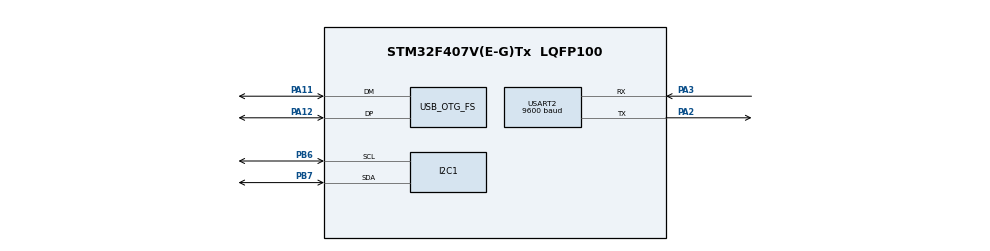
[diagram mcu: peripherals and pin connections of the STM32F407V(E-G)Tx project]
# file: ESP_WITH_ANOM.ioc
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Mcu.Family=STM32F4
Mcu.Name=STM32F407V(E-G)Tx
Mcu.Package=LQFP100
NVIC.OTG_FS_IRQn=true\:0\:0\:false\:false\:true\:true\:true\:true
NVIC.PriorityGroup=NVIC_PRIORITYGROUP_0
PA11.Mode=Device_Only
PA11.Signal=USB_OTG_FS_DM
PA12.Mode=Device_Only
PA12.Signal=USB_OTG_FS_DP
PA13.Mode=Serial_Wire
PA13.Signal=SYS_JTMS-SWDIO
PA14.Mode=Serial_Wire
PA14.Signal=SYS_JTCK-SWCLK
PA2.Mode=Asynchronous
PA2.Signal=USART2_TX
PA3.Mode=Asynchronous
PA3.Signal=USART2_RX
PB6.Mode=I2C
PB6.Signal=I2C1_SCL
PB7.Mode=I2C
PB7.Signal=I2C1_SDA
PH0-OSC_IN.Mode=HSE-External-Oscillator
PH0-OSC_IN.Signal=RCC_OSC_IN
PH1-OSC_OUT.Mode=HSE-External-Oscillator
PH1-OSC_OUT.Signal=RCC_OSC_OUT
ProjectManager.HeapSize=0x200
ProjectManager.StackSize=0x400
ProjectManager.TargetToolchain=STM32CubeIDE
RCC.48MHZClocksFreq_Value=48000000
RCC.AHBFreq_Value=168000000
RCC.APB1CLKDivider=RCC_HCLK_DIV4
RCC.APB1Freq_Value=42000000
RCC.APB1TimFreq_Value=84000000
RCC.APB2CLKDivider=RCC_HCLK_DIV2
RCC.APB2Freq_Value=84000000
RCC.APB2TimFreq_Value=168000000
RCC.CortexFreq_Value=168000000
RCC.HCLKFreq_Value=168000000
RCC.HSE_VALUE=8000000
RCC.HSI_VALUE=16000000
RCC.LSE_VALUE=32768
RCC.PLLM=8
RCC.PLLN=336
RCC.PLLQ=7
RCC.SYSCLKFreq_VALUE=168000000
RCC.SYSCLKSource=RCC_SYSCLKSOURCE_PLLCLK
RCC.VCOOutputFreq_Value=336000000
USART2.BaudRate=9600
USART2.Mode=MODE_TX
USART2.VirtualMode=VM_ASYNC
USB_DEVICE.CLASS_NAME_FS=CDC
USB_DEVICE.VirtualMode-CDC_FS=Cdc
USB_DEVICE.VirtualModeFS=Cdc_FS
USB_OTG_FS.VirtualMode=Device_Only
VP_USB_DEVICE_VS_USB_DEVICE_CDC_FS.Mode=CDC_FS
board=STM32F407G-DISC1

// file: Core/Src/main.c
/* USER CODE BEGIN Header */
/**
  ******************************************************************************
  * @file           : main.c
  * @brief          : Main program body (ADXL345 + USART2 for ESP32)
  ******************************************************************************
  */
/* USER CODE END Header */

#include "main.h"
#include "i2c.h"
#include "usart.h"
#include "gpio.h"

/* USER CODE BEGIN Includes */
#include <stdio.h>
#include <string.h>
#include <stdarg.h>
#include "NanoEdgeAI.h"
#include "knowledge.h"
/* USER CODE END Includes */

/* USER CODE BEGIN PTD */
typedef struct { int16_t x, y, z; } vector3_t;
/* USER CODE END PTD */

/* USER CODE BEGIN PD */
#define ADXL345_ADDR              (0x53 << 1)
#define ADXL345_REG_POWER_CTL     0x2D
#define ADXL345_REG_DATA_FORMAT   0x31
#define ADXL345_REG_DATA_X0       0x32
#define ACC_BUFFER_SIZE           300
/* USER CODE END PD */

/* USER CODE BEGIN PV */
float acc_buffer[ACC_BUFFER_SIZE];
/* USER CODE END PV */

void SystemClock_Config(void);
/* USER CODE BEGIN PFP */
void uart_printf(const char *fmt, ...);
HAL_StatusTypeDef Read_ADXL345(vector3_t *accel);
void fill_accelerometer_buffer(void);
/* USER CODE END PFP */

/* USER CODE BEGIN 0 */
void uart_printf(const char *fmt, ...) {
    char buffer[128];
    va_list args;
    va_start(args, fmt);
    vsnprintf(buffer, sizeof(buffer), fmt, args);
    va_end(args);
    HAL_UART_Transmit(&huart2, (uint8_t *)buffer, strlen(buffer), HAL_MAX_DELAY);
    HAL_Delay(5);
}

HAL_StatusTypeDef Read_ADXL345(vector3_t *accel) {
    uint8_t buf[6];
    if (HAL_I2C_Mem_Read(&hi2c1, ADXL345_ADDR, ADXL345_REG_DATA_X0, 1, buf, 6, 100) != HAL_OK)
        return HAL_ERROR;

    accel->x = (int16_t)((buf[1] << 8) | buf[0]);
    accel->y = (int16_t)((buf[3] << 8) | buf[2]);
    accel->z = (int16_t)((buf[5] << 8) | buf[4]);

    return HAL_OK;
}

void fill_accelerometer_buffer(void) {
    vector3_t acc;
    for (int i = 0; i < ACC_BUFFER_SIZE / 3; i++) {
        while (Read_ADXL345(&acc) != HAL_OK);
        acc_buffer[i * 3 + 0] = acc.x * 0.0039f;
        acc_buffer[i * 3 + 1] = acc.y * 0.0039f;
        acc_buffer[i * 3 + 2] = acc.z * 0.0039f;
        HAL_Delay(1);  // 1kHz sampling
    }
}
/* USER CODE END 0 */

int main(void)
{
  HAL_Init();
  SystemClock_Config();

  MX_GPIO_Init();
  MX_I2C1_Init();
  MX_USART2_UART_Init();

  HAL_Delay(500);
  uart_printf("STM32 UART Ready\r\n");

  /* === ADXL345 INIT === */
  uint8_t cmd;
  cmd = 0x08; // Measure mode
  HAL_I2C_Mem_Write(&hi2c1, ADXL345_ADDR, ADXL345_REG_POWER_CTL, 1, &cmd, 1, 100);
  cmd = 0x08; // ±2g full resolution
  HAL_I2C_Mem_Write(&hi2c1, ADXL345_ADDR, ADXL345_REG_DATA_FORMAT, 1, &cmd, 1, 100);
  HAL_Delay(100);

  /* === NanoEdge AI Initialization === */
  enum neai_state error_code = neai_anomalydetection_init();
  uart_printf("NanoEdgeAI init: %s\r\n", error_code == NEAI_OK ? "OK" : "ERROR");

  /* === Learning Phase === */
  for (uint16_t i = 0; i < 20; i++) {
    uart_printf("Learning iteration %d/20\r\n", i + 1);
    fill_accelerometer_buffer();
    neai_anomalydetection_learn(acc_buffer);
  }

  uart_printf("Learning finished\r\n");

  /* === Inference Phase === */
  uint8_t similarity = 0;

  while (1)
  {
    fill_accelerometer_buffer();
    neai_anomalydetection_detect(acc_buffer, &similarity);

    if (similarity >= 90) {
        uart_printf("NOMINAL,%d\r\n", similarity);
    } else {
        uart_printf("ANOMALY,%d\r\n", similarity);
    }

    HAL_Delay(500);
  }
}

void SystemClock_Config(void)
{
  RCC_OscInitTypeDef RCC_OscInitStruct = {0};
  RCC_ClkInitTypeDef RCC_ClkInitStruct = {0};

  __HAL_RCC_PWR_CLK_ENABLE();
  __HAL_PWR_VOLTAGESCALING_CONFIG(PWR_REGULATOR_VOLTAGE_SCALE1);

  RCC_OscInitStruct.OscillatorType = RCC_OSCILLATORTYPE_HSE;
  RCC_OscInitStruct.HSEState = RCC_HSE_ON;
  RCC_OscInitStruct.PLL.PLLState = RCC_PLL_ON;
  RCC_OscInitStruct.PLL.PLLSource = RCC_PLLSOURCE_HSE;
  RCC_OscInitStruct.PLL.PLLM = 4;
  RCC_OscInitStruct.PLL.PLLN = 72;
  RCC_OscInitStruct.PLL.PLLP = RCC_PLLP_DIV2;
  RCC_OscInitStruct.PLL.PLLQ = 3;

  if (HAL_RCC_OscConfig(&RCC_OscInitStruct) != HAL_OK)
    Error_Handler();

  RCC_ClkInitStruct.ClockType = RCC_CLOCKTYPE_HCLK | RCC_CLOCKTYPE_SYSCLK |
                                RCC_CLOCKTYPE_PCLK1 | RCC_CLOCKTYPE_PCLK2;
  RCC_ClkInitStruct.SYSCLKSource = RCC_SYSCLKSOURCE_PLLCLK;
  RCC_ClkInitStruct.AHBCLKDivider = RCC_SYSCLK_DIV1;
  RCC_ClkInitStruct.APB1CLKDivider = RCC_HCLK_DIV2;
  RCC_ClkInitStruct.APB2CLKDivider = RCC_HCLK_DIV1;

  if (HAL_RCC_ClockConfig(&RCC_ClkInitStruct, FLASH_LATENCY_2) != HAL_OK)
    Error_Handler();
}

void Error_Handler(void)
{
  __disable_irq();
  while (1) {}
}
